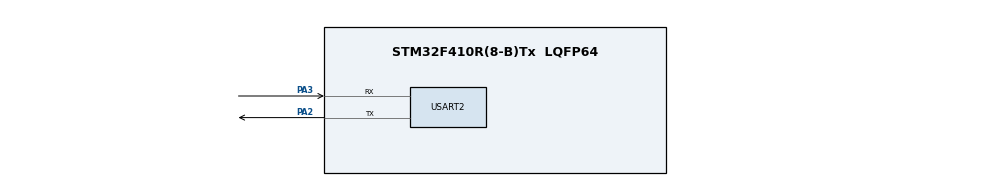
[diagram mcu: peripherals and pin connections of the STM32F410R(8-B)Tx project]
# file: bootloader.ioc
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Mcu.Family=STM32F4
Mcu.Name=STM32F410R(8-B)Tx
Mcu.Package=LQFP64
NVIC.PriorityGroup=NVIC_PRIORITYGROUP_4
PA13.Mode=Serial_Wire
PA13.Signal=SYS_JTMS-SWDIO
PA14.Mode=Serial_Wire
PA14.Signal=SYS_JTCK-SWCLK
PA2.Mode=Asynchronous
PA2.Signal=USART2_TX
PA3.Mode=Asynchronous
PA3.Signal=USART2_RX
PC14-OSC32_IN.Mode=LSE-External-Oscillator
PC14-OSC32_IN.Signal=RCC_OSC32_IN
PC15-OSC32_OUT.Mode=LSE-External-Oscillator
PC15-OSC32_OUT.Signal=RCC_OSC32_OUT
PH0\ -\ OSC_IN.Mode=HSE-External-Oscillator
PH0\ -\ OSC_IN.Signal=RCC_OSC_IN
PH1\ -\ OSC_OUT.Mode=HSE-External-Oscillator
PH1\ -\ OSC_OUT.Signal=RCC_OSC_OUT
ProjectManager.HeapSize=0x200
ProjectManager.StackSize=0x400
ProjectManager.TargetToolchain=Makefile
RCC.48MHZClocksFreq_Value=50000000
RCC.AHBFreq_Value=100000000
RCC.APB1CLKDivider=RCC_HCLK_DIV2
RCC.APB1Freq_Value=50000000
RCC.APB1TimFreq_Value=100000000
RCC.APB2Freq_Value=100000000
RCC.APB2TimFreq_Value=100000000
RCC.CortexFreq_Value=100000000
RCC.HCLKFreq_Value=100000000
RCC.HSE_VALUE=25000000
RCC.HSI_VALUE=16000000
RCC.PLLM=12
RCC.PLLN=96
RCC.PLLSourceVirtual=RCC_PLLSOURCE_HSE
RCC.SYSCLKFreq_VALUE=100000000
RCC.SYSCLKSource=RCC_SYSCLKSOURCE_PLLCLK
RCC.VCOOutputFreq_Value=200000000
USART2.VirtualMode=VM_ASYNC
board=custom

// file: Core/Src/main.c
/* USER CODE BEGIN Header */
/**
  ******************************************************************************
  * @file           : main.c
  * @brief          : Main program body
  ******************************************************************************
  * @attention
  *
  * Copyright (c) 2025 STMicroelectronics.
  * All rights reserved.
  *
  * This software is licensed under terms that can be found in the LICENSE file
  * in the root directory of this software component.
  * If no LICENSE file comes with this software, it is provided AS-IS.
  *
  ******************************************************************************
  */
/* USER CODE END Header */
#include "main.h"
#include "usart.h"
#include "gpio.h"

/* USER CODE BEGIN Includes */
#include <stdio.h>
#include <stdint.h>
#include <stdbool.h>
#include <stddef.h>
#include "FLASH_SECTOR_F4.h"
/* USER CODE END Includes */

void SystemClock_Config(void);

/* USER CODE BEGIN 0 */
int __io_putchar(int ch)
{
  if (ch == '\n')
  {
    HAL_UART_Transmit(&huart2, (uint8_t *)"\r\n", 2, 1000);
  }
  HAL_UART_Transmit(&huart2, (uint8_t *)&ch, 1, 1000);
  return ch;
}

static bool is_fwu_needed(void)
{
  return false;
}

static void start_app(void)
{
  // reset peripherals
  HAL_DeInit();

  uint32_t *app_vector_addr = (uint32_t*)0x08004000;
  uint32_t sp = app_vector_addr[0];
  uint32_t pc = app_vector_addr[1];
  asm volatile("msr msp, %0\n"
               "msr psp, %0\n"
               "bx %1\n"
               :
               : "r"(sp), "r"(pc));
  __builtin_unreachable();
}

/* USER CODE END 0 */

int main(void)
{

  /* MCU Configuration--------------------------------------------------------*/

  /* Reset of all peripherals, Initializes the Flash interface and the Systick. */
  HAL_Init();

  /* Configure the system clock */
  SystemClock_Config();

  /* Initialize all configured peripherals */
  MX_GPIO_Init();
  MX_USART2_UART_Init();
  /* USER CODE BEGIN 2 */
  printf("bootloader\r\n");
  if (!is_fwu_needed())
  {
    printf("fwu not needed\r\n");
    start_app();
  }
  else
  {
    printf("fwu needed\r\n");
    // fwu_process();
  }
  /* USER CODE END 2 */

  /* Infinite loop */
  while (1)
  {

  }
}

void SystemClock_Config(void)
{
  RCC_OscInitTypeDef RCC_OscInitStruct = {0};
  RCC_ClkInitTypeDef RCC_ClkInitStruct = {0};

  /** Configure the main internal regulator output voltage
  */
  __HAL_RCC_PWR_CLK_ENABLE();
  __HAL_PWR_VOLTAGESCALING_CONFIG(PWR_REGULATOR_VOLTAGE_SCALE1);

  /** Initializes the RCC Oscillators according to the specified parameters
  * in the RCC_OscInitTypeDef structure.
  */
  RCC_OscInitStruct.OscillatorType = RCC_OSCILLATORTYPE_HSE;
  RCC_OscInitStruct.HSEState = RCC_HSE_ON;
  RCC_OscInitStruct.PLL.PLLState = RCC_PLL_ON;
  RCC_OscInitStruct.PLL.PLLSource = RCC_PLLSOURCE_HSE;
  RCC_OscInitStruct.PLL.PLLM = 4;
  RCC_OscInitStruct.PLL.PLLN = 100;
  RCC_OscInitStruct.PLL.PLLP = RCC_PLLP_DIV2;
  RCC_OscInitStruct.PLL.PLLQ = 4;
  RCC_OscInitStruct.PLL.PLLR = 2;
  if (HAL_RCC_OscConfig(&RCC_OscInitStruct) != HAL_OK)
  {
    Error_Handler();
  }

  /** Initializes the CPU, AHB and APB buses clocks
  */
  RCC_ClkInitStruct.ClockType = RCC_CLOCKTYPE_HCLK|RCC_CLOCKTYPE_SYSCLK
                              |RCC_CLOCKTYPE_PCLK1|RCC_CLOCKTYPE_PCLK2;
  RCC_ClkInitStruct.SYSCLKSource = RCC_SYSCLKSOURCE_PLLCLK;
  RCC_ClkInitStruct.AHBCLKDivider = RCC_SYSCLK_DIV1;
  RCC_ClkInitStruct.APB1CLKDivider = RCC_HCLK_DIV2;
  RCC_ClkInitStruct.APB2CLKDivider = RCC_HCLK_DIV1;

  if (HAL_RCC_ClockConfig(&RCC_ClkInitStruct, FLASH_LATENCY_3) != HAL_OK)
  {
    Error_Handler();
  }
}

void Error_Handler(void)
{
  __disable_irq();
  while (1)
  {
  }
}
